VERSION 5.7 ;
  NOWIREEXTENSIONATPIN ON ;
  DIVIDERCHAR "/" ;
  BUSBITCHARS "[]" ;
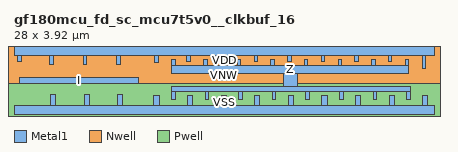
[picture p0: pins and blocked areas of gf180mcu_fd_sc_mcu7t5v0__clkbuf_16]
MACRO gf180mcu_fd_sc_mcu7t5v0__clkbuf_16
  CLASS core ;
  FOREIGN gf180mcu_fd_sc_mcu7t5v0__clkbuf_16 ;
  ORIGIN 0.000 0.000 ;
  SIZE 28.000 BY 3.920 ;
  SYMMETRY X Y ;
  SITE GF018hv5v_mcu_sc7 ;
  PIN I
    DIRECTION INPUT ;
    ANTENNAGATEAREA 4.738000 ;
    PORT
      LAYER Metal1 ;
        RECT 0.370 1.740 8.310 2.150 ;
    END
  END I
  PIN Z
    DIRECTION OUTPUT ;
    ANTENNADIFFAREA 8.068800 ;
    PORT
      LAYER Metal1 ;
        RECT 10.505 3.000 10.735 3.390 ;
        RECT 12.645 3.000 12.875 3.390 ;
        RECT 14.885 3.000 15.115 3.390 ;
        RECT 17.125 3.000 17.355 3.390 ;
        RECT 19.365 3.000 19.595 3.390 ;
        RECT 21.605 3.000 21.835 3.390 ;
        RECT 23.845 3.000 24.075 3.390 ;
        RECT 26.085 3.000 26.315 3.390 ;
        RECT 10.505 2.420 26.315 3.000 ;
        RECT 17.985 1.535 18.885 2.420 ;
        RECT 10.505 1.215 26.415 1.535 ;
        RECT 10.505 0.690 10.735 1.215 ;
        RECT 12.745 0.690 12.975 1.215 ;
        RECT 14.985 0.690 15.215 1.215 ;
        RECT 17.225 0.690 17.455 1.215 ;
        RECT 19.465 0.690 19.695 1.215 ;
        RECT 21.705 0.690 21.935 1.215 ;
        RECT 23.945 0.690 24.175 1.215 ;
        RECT 26.185 0.690 26.415 1.215 ;
    END
  END Z
  PIN VDD
    DIRECTION INOUT ;
    USE POWER ;
    SHAPE ABUTMENT ;
    PORT
      LAYER Metal1 ;
        RECT 0.000 3.620 28.000 4.220 ;
        RECT 0.245 3.230 0.475 3.620 ;
        RECT 2.385 3.050 2.615 3.620 ;
        RECT 4.625 3.050 4.855 3.620 ;
        RECT 6.865 3.050 7.095 3.620 ;
        RECT 9.385 3.190 9.615 3.620 ;
        RECT 11.525 3.230 11.755 3.620 ;
        RECT 13.765 3.230 13.995 3.620 ;
        RECT 16.005 3.230 16.235 3.620 ;
        RECT 18.245 3.230 18.475 3.620 ;
        RECT 20.485 3.230 20.715 3.620 ;
        RECT 22.725 3.230 22.955 3.620 ;
        RECT 24.965 3.230 25.195 3.620 ;
        RECT 27.205 2.760 27.435 3.620 ;
    END
  END VDD
  PIN VNW
    DIRECTION INOUT ;
    USE POWER ;
    PORT
      LAYER Nwell ;
        RECT -0.430 1.760 28.430 4.350 ;
    END
  END VNW
  PIN VPW
    DIRECTION INOUT ;
    USE GROUND ;
    PORT
      LAYER Pwell ;
        RECT -0.430 -0.430 28.430 1.760 ;
    END
  END VPW
  PIN VSS
    DIRECTION INOUT ;
    USE GROUND ;
    SHAPE ABUTMENT ;
    PORT
      LAYER Metal1 ;
        RECT 2.430 0.300 2.770 1.040 ;
        RECT 4.670 0.300 5.010 1.040 ;
        RECT 6.910 0.300 7.250 1.040 ;
        RECT 9.330 0.300 9.670 0.960 ;
        RECT 11.570 0.300 11.910 0.985 ;
        RECT 13.810 0.300 14.150 0.985 ;
        RECT 16.050 0.300 16.390 0.985 ;
        RECT 18.290 0.300 18.630 0.985 ;
        RECT 20.530 0.300 20.870 0.985 ;
        RECT 22.770 0.300 23.110 0.985 ;
        RECT 25.010 0.300 25.350 0.985 ;
        RECT 27.250 0.300 27.590 0.985 ;
        RECT 0.000 -0.300 28.000 0.300 ;
    END
  END VSS
  OBS
      LAYER Metal1 ;
        RECT 1.265 2.760 1.495 3.390 ;
        RECT 3.505 2.760 3.735 3.390 ;
        RECT 5.745 2.760 5.975 3.390 ;
        RECT 7.985 2.760 8.215 3.390 ;
        RECT 1.265 2.530 8.850 2.760 ;
        RECT 8.620 2.065 8.850 2.530 ;
        RECT 8.620 1.765 17.160 2.065 ;
        RECT 19.740 1.765 27.160 2.065 ;
        RECT 8.620 1.500 8.850 1.765 ;
        RECT 1.365 1.270 8.850 1.500 ;
        RECT 1.365 0.740 1.595 1.270 ;
        RECT 3.605 0.740 3.835 1.270 ;
        RECT 5.845 0.740 6.075 1.270 ;
        RECT 8.085 0.740 8.315 1.270 ;
  END
END gf180mcu_fd_sc_mcu7t5v0__clkbuf_16

END LIBRARY
